VERSION 5.8 ;
BUSBITCHARS "[]" ;
DIVIDERCHAR "/" ;

PROPERTYDEFINITIONS
  MACRO SDLpower STRING ;
  MACRO SDLground STRING ;
  MACRO SDLglobal STRING ;
END PROPERTYDEFINITIONS

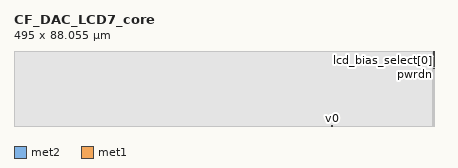
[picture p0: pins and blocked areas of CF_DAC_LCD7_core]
MACRO CF_DAC_LCD7_core
  CLASS BLOCK ;
  ORIGIN 0 0 ;
  FOREIGN CF_DAC_LCD7_core 0 0 ;
  SIZE 495 BY 88.055 ;
  PIN vpwr_lv_int
    DIRECTION OUTPUT ;
    USE SIGNAL ;
    PORT
      LAYER met2 ;
        RECT 494.025 72.575 495 72.835 ;
    END
  END vpwr_lv_int
  PIN continuous_drive
    DIRECTION INPUT ;
    USE SIGNAL ;
    PORT
      LAYER met1 ;
        RECT 494.075 80.215 495 80.475 ;
    END
  END continuous_drive
  PIN holdb
    DIRECTION INPUT ;
    USE SIGNAL ;
    PORT
      LAYER met1 ;
        RECT 494.01 74.415 495 74.675 ;
    END
  END holdb
  PIN v4
    DIRECTION OUTPUT ;
    USE SIGNAL ;
    PORT
      LAYER met1 ;
        RECT 373.775 0 373.915 0.29 ;
    END
  END v4
  PIN v3
    DIRECTION OUTPUT ;
    USE SIGNAL ;
    PORT
      LAYER met1 ;
        RECT 374.115 0 374.255 0.29 ;
    END
  END v3
  PIN v2
    DIRECTION OUTPUT ;
    USE SIGNAL ;
    PORT
      LAYER met1 ;
        RECT 374.455 0 374.595 0.29 ;
    END
  END v2
  PIN v1
    DIRECTION OUTPUT ;
    USE SIGNAL ;
    PORT
      LAYER met1 ;
        RECT 374.795 0 374.935 0.29 ;
    END
  END v1
  PIN v0
    DIRECTION OUTPUT ;
    USE SIGNAL ;
    PORT
      LAYER met1 ;
        RECT 375.135 0 375.275 0.29 ;
    END
  END v0
  PIN pwrdn
    DIRECTION INPUT ;
    USE SIGNAL ;
    PORT
      LAYER met1 ;
        RECT 494.085 70.03 495 70.29 ;
    END
  END pwrdn
  PIN vpwr_ao
    DIRECTION INPUT ;
    USE SIGNAL ;
    PORT
      LAYER met1 ;
        RECT 494.08 75.06 495 75.32 ;
    END
  END vpwr_ao
  PIN vpb_hv
    DIRECTION INPUT ;
    USE SIGNAL ;
    PORT
      LAYER met1 ;
        RECT 494.025 73.47 495 74.05 ;
    END
  END vpb_hv
  PIN vpwr_hv
    DIRECTION INPUT ;
    USE SIGNAL ;
    PORT
      LAYER met2 ;
        RECT 493.6 81.195 495 82.695 ;
    END
  END vpwr_hv
  PIN vnb
    DIRECTION INPUT ;
    USE GROUND ;
    PORT
      LAYER met1 ;
        RECT 494.02 87.415 495 87.675 ;
    END
  END vnb
  PIN vgnd
    DIRECTION INPUT ;
    USE GROUND ;
    PORT
      LAYER met2 ;
        RECT 494.02 85.935 495 87.215 ;
    END
  END vgnd
  PIN vpb_lv
    DIRECTION INPUT ;
    USE SIGNAL ;
    PORT
      LAYER met1 ;
        RECT 494.085 70.675 495 70.935 ;
    END
  END vpb_lv
  PIN enable_hv
    DIRECTION INPUT ;
    USE SIGNAL ;
    PORT
      LAYER met1 ;
        RECT 494.075 67.46 495 67.72 ;
    END
  END enable_hv
  PIN lcd_bias_select[0]
    DIRECTION INPUT ;
    USE SIGNAL ;
    PORT
      LAYER met1 ;
        RECT 494.095 83.445 495 83.705 ;
    END
  END lcd_bias_select[0]
  PIN lcd_bias_select[1]
    DIRECTION INPUT ;
    USE SIGNAL ;
    PORT
      LAYER met1 ;
        RECT 494.095 84.085 495 84.345 ;
    END
  END lcd_bias_select[1]
  PIN d[6]
    DIRECTION INPUT ;
    USE SIGNAL ;
    PORT
      LAYER met1 ;
        RECT 494.045 75.705 495 75.965 ;
    END
  END d[6]
  PIN d[5]
    DIRECTION INPUT ;
    USE SIGNAL ;
    PORT
      LAYER met1 ;
        RECT 494.045 76.35 495 76.61 ;
    END
  END d[5]
  PIN d[4]
    DIRECTION INPUT ;
    USE SIGNAL ;
    PORT
      LAYER met1 ;
        RECT 494.045 76.995 495 77.255 ;
    END
  END d[4]
  PIN d[3]
    DIRECTION INPUT ;
    USE SIGNAL ;
    PORT
      LAYER met1 ;
        RECT 494.045 77.635 495 77.895 ;
    END
  END d[3]
  PIN d[2]
    DIRECTION INPUT ;
    USE SIGNAL ;
    PORT
      LAYER met1 ;
        RECT 494.045 78.275 495 78.535 ;
    END
  END d[2]
  PIN d[1]
    DIRECTION INPUT ;
    USE SIGNAL ;
    PORT
      LAYER met1 ;
        RECT 494.005 78.92 495 79.18 ;
    END
  END d[1]
  PIN vpwr_lv
    DIRECTION INPUT ;
    USE SIGNAL ;
    PORT
      LAYER met2 ;
        RECT 494.07 71.44 495 71.7 ;
    END
  END vpwr_lv
  PIN d[0]
    DIRECTION INPUT ;
    USE SIGNAL ;
    PORT
      LAYER met1 ;
        RECT 494.025 79.56 495 79.82 ;
    END
  END d[0]
  PROPERTY SDLpower "vpwr_hv" ;
  PROPERTY SDLground "vgnd" ;
  PROPERTY SDLglobal "" ;
  OBS
    LAYER li1 ;
      RECT 0 0 495 88.055 ;
    LAYER met1 ;
      RECT 0 0 373.775 88.055 ;
      RECT 373.775 0.29 373.915 88.055 ;
      RECT 373.915 0 374.115 88.055 ;
      RECT 374.115 0.29 374.255 88.055 ;
      RECT 374.255 0 374.455 88.055 ;
      RECT 374.455 0.29 374.595 88.055 ;
      RECT 374.595 0 374.795 88.055 ;
      RECT 374.795 0.29 374.935 88.055 ;
      RECT 374.935 0 375.135 88.055 ;
      RECT 375.135 0.29 375.275 88.055 ;
      RECT 375.275 0 494.005 88.055 ;
      RECT 494.005 0 494.01 78.92 ;
      RECT 494.005 79.18 494.01 88.055 ;
      RECT 494.01 0 494.02 74.415 ;
      RECT 494.01 74.675 494.02 78.92 ;
      RECT 494.01 79.18 494.02 88.055 ;
      RECT 494.02 0 494.025 74.415 ;
      RECT 494.02 74.675 494.025 78.92 ;
      RECT 494.02 79.18 494.025 87.415 ;
      RECT 494.02 87.675 494.025 88.055 ;
      RECT 494.025 0 494.045 73.47 ;
      RECT 494.025 74.05 494.045 74.415 ;
      RECT 494.025 74.675 494.045 78.92 ;
      RECT 494.025 79.18 494.045 79.56 ;
      RECT 494.025 79.82 494.045 87.415 ;
      RECT 494.025 87.675 494.045 88.055 ;
      RECT 494.045 0 494.075 73.47 ;
      RECT 494.045 74.05 494.075 74.415 ;
      RECT 494.045 74.675 494.075 75.705 ;
      RECT 494.045 75.965 494.075 76.35 ;
      RECT 494.045 76.61 494.075 76.995 ;
      RECT 494.045 77.255 494.075 77.635 ;
      RECT 494.045 77.895 494.075 78.275 ;
      RECT 494.045 78.535 494.075 78.92 ;
      RECT 494.045 79.18 494.075 79.56 ;
      RECT 494.045 79.82 494.075 87.415 ;
      RECT 494.045 87.675 494.075 88.055 ;
      RECT 494.075 0 494.08 67.46 ;
      RECT 494.075 67.72 494.08 73.47 ;
      RECT 494.075 74.05 494.08 74.415 ;
      RECT 494.075 74.675 494.08 75.705 ;
      RECT 494.075 75.965 494.08 76.35 ;
      RECT 494.075 76.61 494.08 76.995 ;
      RECT 494.075 77.255 494.08 77.635 ;
      RECT 494.075 77.895 494.08 78.275 ;
      RECT 494.075 78.535 494.08 78.92 ;
      RECT 494.075 79.18 494.08 79.56 ;
      RECT 494.075 79.82 494.08 80.215 ;
      RECT 494.075 80.475 494.08 87.415 ;
      RECT 494.075 87.675 494.08 88.055 ;
      RECT 494.08 0 494.085 67.46 ;
      RECT 494.08 67.72 494.085 73.47 ;
      RECT 494.08 74.05 494.085 74.415 ;
      RECT 494.08 74.675 494.085 75.06 ;
      RECT 494.08 75.32 494.085 75.705 ;
      RECT 494.08 75.965 494.085 76.35 ;
      RECT 494.08 76.61 494.085 76.995 ;
      RECT 494.08 77.255 494.085 77.635 ;
      RECT 494.08 77.895 494.085 78.275 ;
      RECT 494.08 78.535 494.085 78.92 ;
      RECT 494.08 79.18 494.085 79.56 ;
      RECT 494.08 79.82 494.085 80.215 ;
      RECT 494.08 80.475 494.085 87.415 ;
      RECT 494.08 87.675 494.085 88.055 ;
      RECT 494.085 0 494.095 67.46 ;
      RECT 494.085 67.72 494.095 70.03 ;
      RECT 494.085 70.29 494.095 70.675 ;
      RECT 494.085 70.935 494.095 73.47 ;
      RECT 494.085 74.05 494.095 74.415 ;
      RECT 494.085 74.675 494.095 75.06 ;
      RECT 494.085 75.32 494.095 75.705 ;
      RECT 494.085 75.965 494.095 76.35 ;
      RECT 494.085 76.61 494.095 76.995 ;
      RECT 494.085 77.255 494.095 77.635 ;
      RECT 494.085 77.895 494.095 78.275 ;
      RECT 494.085 78.535 494.095 78.92 ;
      RECT 494.085 79.18 494.095 79.56 ;
      RECT 494.085 79.82 494.095 80.215 ;
      RECT 494.085 80.475 494.095 87.415 ;
      RECT 494.085 87.675 494.095 88.055 ;
      RECT 494.095 0 495 67.46 ;
      RECT 494.095 67.72 495 70.03 ;
      RECT 494.095 70.29 495 70.675 ;
      RECT 494.095 70.935 495 73.47 ;
      RECT 494.095 74.05 495 74.415 ;
      RECT 494.095 74.675 495 75.06 ;
      RECT 494.095 75.32 495 75.705 ;
      RECT 494.095 75.965 495 76.35 ;
      RECT 494.095 76.61 495 76.995 ;
      RECT 494.095 77.255 495 77.635 ;
      RECT 494.095 77.895 495 78.275 ;
      RECT 494.095 78.535 495 78.92 ;
      RECT 494.095 79.18 495 79.56 ;
      RECT 494.095 79.82 495 80.215 ;
      RECT 494.095 80.475 495 83.445 ;
      RECT 494.095 83.705 495 84.085 ;
      RECT 494.095 84.345 495 87.415 ;
      RECT 494.095 87.675 495 88.055 ;
    LAYER met2 ;
      RECT 0 0 493.6 88.055 ;
      RECT 493.6 0 494.02 81.195 ;
      RECT 493.6 82.695 494.02 88.055 ;
      RECT 494.02 0 494.025 81.195 ;
      RECT 494.02 82.695 494.025 85.935 ;
      RECT 494.02 87.215 494.025 88.055 ;
      RECT 494.025 0 494.07 72.575 ;
      RECT 494.025 72.835 494.07 81.195 ;
      RECT 494.025 82.695 494.07 85.935 ;
      RECT 494.025 87.215 494.07 88.055 ;
      RECT 494.07 0 495 71.44 ;
      RECT 494.07 71.7 495 72.575 ;
      RECT 494.07 72.835 495 81.195 ;
      RECT 494.07 82.695 495 85.935 ;
      RECT 494.07 87.215 495 88.055 ;
  END
END CF_DAC_LCD7_core

END LIBRARY
